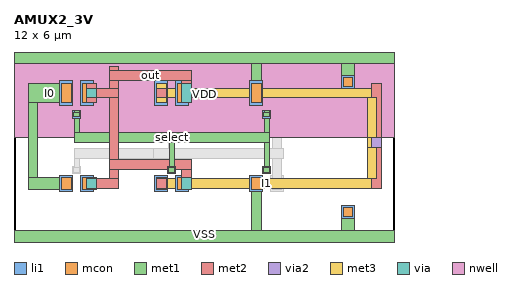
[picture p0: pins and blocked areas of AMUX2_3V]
MACRO AMUX2_3V
  CLASS BLOCK ;
  FOREIGN AMUX2_3V ;
  ORIGIN 0.000 0.000 ;
  SIZE 12.000 BY 6.000 ;
  PIN I0
    DIRECTION INPUT ;
    USE SIGNAL ;
    ANTENNADIFFAREA 0.750000 ;
    PORT
      LAYER li1 ;
        RECT 1.450 4.300 1.850 5.100 ;
        RECT 1.450 1.600 1.850 2.100 ;
      LAYER mcon ;
        RECT 1.500 4.400 1.800 5.000 ;
        RECT 1.500 1.650 1.800 2.050 ;
      LAYER met1 ;
        RECT 0.450 4.400 1.800 5.000 ;
        RECT 0.450 2.050 0.750 4.400 ;
        RECT 0.450 1.650 1.800 2.050 ;
    END
  END I0
  PIN I1
    DIRECTION INPUT ;
    USE SIGNAL ;
    ANTENNADIFFAREA 0.750000 ;
    PORT
      LAYER li1 ;
        RECT 4.450 4.300 4.850 5.100 ;
        RECT 4.450 1.600 4.850 2.100 ;
      LAYER mcon ;
        RECT 4.500 4.400 4.800 5.000 ;
        RECT 4.500 1.650 4.800 2.050 ;
      LAYER met1 ;
        RECT 4.500 4.400 4.800 5.000 ;
        RECT 4.500 1.650 4.800 2.050 ;
      LAYER met2 ;
        RECT 4.500 4.400 4.800 5.000 ;
        RECT 4.500 1.650 4.800 2.050 ;
        RECT 11.300 1.700 11.600 5.000 ;
      LAYER via2 ;
        RECT 11.300 3.000 11.600 3.300 ;
      LAYER met3 ;
        RECT 4.500 4.850 4.800 5.000 ;
        RECT 4.500 4.550 11.450 4.850 ;
        RECT 4.500 4.400 4.800 4.550 ;
        RECT 11.150 3.300 11.450 4.550 ;
        RECT 11.150 3.000 11.600 3.300 ;
        RECT 4.500 2.000 4.800 2.050 ;
        RECT 11.150 2.000 11.450 3.000 ;
        RECT 4.500 1.700 11.450 2.000 ;
        RECT 4.500 1.650 4.800 1.700 ;
    END
  END I1
  PIN select
    DIRECTION INPUT ;
    USE SIGNAL ;
    ANTENNAGATEAREA 0.450000 ;
    PORT
      LAYER li1 ;
        RECT 1.850 3.900 2.100 4.150 ;
        RECT 7.850 3.900 8.100 4.150 ;
        RECT 4.850 2.150 5.100 2.400 ;
        RECT 7.850 2.150 8.100 2.400 ;
      LAYER mcon ;
        RECT 1.880 3.950 2.070 4.100 ;
        RECT 7.880 3.950 8.070 4.100 ;
        RECT 4.880 2.200 5.070 2.350 ;
        RECT 7.880 2.200 8.070 2.350 ;
      LAYER met1 ;
        RECT 1.900 4.100 2.070 4.150 ;
        RECT 7.900 4.100 8.070 4.150 ;
        RECT 1.880 3.950 2.070 4.100 ;
        RECT 7.880 3.950 8.070 4.100 ;
        RECT 1.900 3.450 2.070 3.950 ;
        RECT 7.900 3.450 8.070 3.950 ;
        RECT 1.900 3.150 8.070 3.450 ;
        RECT 4.900 2.350 5.070 3.150 ;
        RECT 7.900 2.350 8.070 3.150 ;
        RECT 4.880 2.200 5.070 2.350 ;
        RECT 7.880 2.200 8.070 2.350 ;
    END
  END select
  PIN out
    DIRECTION OUTPUT ;
    USE SIGNAL ;
    ANTENNADIFFAREA 1.500000 ;
    PORT
      LAYER li1 ;
        RECT 2.100 4.300 2.500 5.100 ;
        RECT 5.100 4.300 5.500 5.100 ;
        RECT 2.100 1.600 2.500 2.100 ;
        RECT 5.100 1.600 5.500 2.100 ;
      LAYER mcon ;
        RECT 2.150 4.400 2.450 5.000 ;
        RECT 5.150 4.400 5.450 5.000 ;
        RECT 2.150 1.650 2.450 2.050 ;
        RECT 5.150 1.650 5.450 2.050 ;
      LAYER met1 ;
        RECT 2.150 4.400 2.600 5.000 ;
        RECT 5.150 4.400 5.600 5.000 ;
        RECT 2.150 1.650 2.600 2.050 ;
        RECT 5.150 1.650 5.600 2.050 ;
      LAYER via ;
        RECT 2.300 4.400 2.600 5.000 ;
        RECT 5.300 4.400 5.600 5.000 ;
        RECT 2.300 1.650 2.600 2.050 ;
        RECT 5.300 1.650 5.600 2.050 ;
      LAYER met2 ;
        RECT 3.000 5.400 3.300 5.550 ;
        RECT 3.000 5.100 5.600 5.400 ;
        RECT 2.300 4.850 2.600 5.000 ;
        RECT 3.000 4.850 3.300 5.100 ;
        RECT 2.300 4.550 3.300 4.850 ;
        RECT 2.300 4.400 2.600 4.550 ;
        RECT 3.000 2.600 3.300 4.550 ;
        RECT 5.300 4.400 5.600 5.100 ;
        RECT 3.000 2.300 5.600 2.600 ;
        RECT 2.300 2.000 2.600 2.050 ;
        RECT 3.000 2.000 3.300 2.300 ;
        RECT 2.300 1.700 3.300 2.000 ;
        RECT 2.300 1.650 2.600 1.700 ;
        RECT 5.300 1.650 5.600 2.300 ;
    END
  END out
  PIN VDD
    DIRECTION INOUT ;
    USE POWER ;
    PORT
      LAYER nwell ;
        RECT 0.000 3.300 12.000 6.000 ;
      LAYER li1 ;
        RECT 7.450 4.300 7.850 5.100 ;
        RECT 10.350 4.850 10.750 5.250 ;
      LAYER mcon ;
        RECT 7.500 4.400 7.800 5.000 ;
        RECT 10.400 4.900 10.700 5.200 ;
      LAYER met1 ;
        RECT 0.000 5.650 12.000 6.000 ;
        RECT 7.500 4.400 7.800 5.650 ;
        RECT 10.350 4.900 10.750 5.650 ;
    END
  END VDD
  PIN VSS
    DIRECTION INOUT ;
    USE GROUND ;
    PORT
      LAYER li1 ;
        RECT 7.450 1.600 7.850 2.100 ;
        RECT 10.350 0.750 10.750 1.150 ;
      LAYER mcon ;
        RECT 7.500 1.650 7.800 2.050 ;
        RECT 10.400 0.800 10.700 1.100 ;
      LAYER met1 ;
        RECT 7.500 0.350 7.800 2.050 ;
        RECT 10.350 0.350 10.750 1.100 ;
        RECT 0.000 0.000 12.000 0.350 ;
    END
  END VSS
  OBS
      LAYER li1 ;
        RECT 8.100 4.300 8.500 5.100 ;
        RECT 4.850 3.900 5.100 4.150 ;
        RECT 1.850 2.150 2.100 2.400 ;
        RECT 8.100 1.600 8.500 2.100 ;
      LAYER mcon ;
        RECT 8.150 4.400 8.450 5.000 ;
        RECT 4.880 3.950 5.070 4.100 ;
        RECT 1.880 2.200 2.070 2.350 ;
        RECT 8.150 1.650 8.450 2.050 ;
      LAYER met1 ;
        RECT 4.900 4.100 5.070 4.150 ;
        RECT 4.880 3.950 5.070 4.100 ;
        RECT 8.150 2.950 8.450 5.000 ;
        RECT 1.900 2.650 4.600 2.950 ;
        RECT 8.150 2.650 8.500 2.950 ;
        RECT 1.900 2.350 2.070 2.650 ;
        RECT 1.880 2.200 2.070 2.350 ;
        RECT 8.150 1.650 8.450 2.650 ;
      LAYER via ;
        RECT 4.400 2.650 4.600 2.950 ;
        RECT 8.300 2.650 8.500 2.950 ;
      LAYER met2 ;
        RECT 4.880 2.950 5.070 4.100 ;
        RECT 4.400 2.650 8.500 2.950 ;
  END
END AMUX2_3V
END LIBRARY

